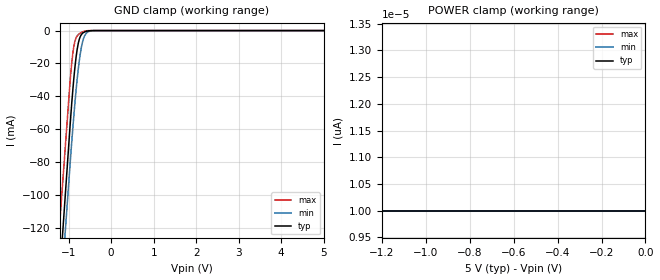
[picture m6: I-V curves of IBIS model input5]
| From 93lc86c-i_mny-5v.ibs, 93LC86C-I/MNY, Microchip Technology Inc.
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|   Model input5
[Model]   input5
Model_type   Input
Vinl = 0.8
Vinh = 2.0
C_comp   5.00pF   5.00pF   5.00pF
[Temperature Range]   25.00   85.00   -40.00
[Voltage Range]   5.00V   2.50V   5.50V
[Pullup Reference]   5.00V   5.00V   5.00V
[POWER Clamp Reference]   5.00V   5.00V   5.00V
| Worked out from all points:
|   GND clamp passes 1 mA (typ) near -0.64 V on its own axis
[GND_clamp]
| voltage   I(typ)   I(min)   I(max)
-5V       -1.573A    -1.537A    -1.46A
-1.25V    -164.3mA   -183.8mA   -131.5mA
-1.1V     -108mA     -129.7mA   -78.31mA
-975mV    -61.05mA   -84.58mA   -34.01mA
-900mV    -35.58mA   -58.86mA   -13.47mA
-850mV    -21.73mA   -43.31mA   -6.235mA
-800mV    -11.49mA   -29.63mA   -3.232mA
-750mV    -5.301mA   -18.38mA   -1.921mA
-675mV    -1.67mA    -7.096mA   -790.8uA
-575mV    -395.6uA   -1.342mA   -105.6uA
-400mV    -3.298uA   -39.22uA   -74.14nA
5V        10pA       10pA       10pA
[POWER_clamp]
| voltage   I(typ)   I(min)   I(max)
-5V       2.109nA    4.531nA    1.336nA
-4.85V    1.48nA     3.6nA      10pA
-4.7V     1.086nA    2.904nA    10pA
-4.55V    10pA       2.426nA    10pA
-3.5V     10pA       1.021nA    10pA
-3.35V    10pA       10pA       10pA
0V        10pA       10pA       10pA
